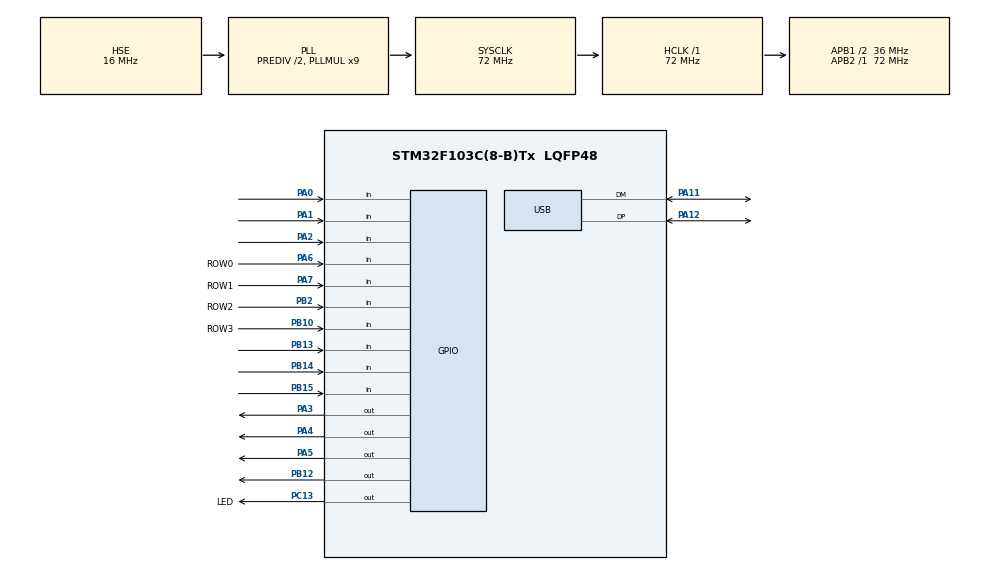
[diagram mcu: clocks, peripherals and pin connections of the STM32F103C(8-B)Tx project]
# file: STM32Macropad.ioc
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Mcu.Family=STM32F1
Mcu.Name=STM32F103C(8-B)Tx
Mcu.Package=LQFP48
NVIC.PriorityGroup=NVIC_PRIORITYGROUP_4
NVIC.USB_LP_CAN1_RX0_IRQn=true\:0\:0\:false\:false\:true\:false\:true\:true
PA0-WKUP.Signal=GPIO_Input
PA1.Signal=GPIO_Input
PA11.Mode=Device
PA11.Signal=USB_DM
PA12.Mode=Device
PA12.Signal=USB_DP
PA13.Mode=Serial_Wire
PA13.Signal=SYS_JTMS-SWDIO
PA14.Mode=Serial_Wire
PA14.Signal=SYS_JTCK-SWCLK
PA2.Signal=GPIO_Input
PA3.Signal=GPIO_Output
PA4.Signal=GPIO_Output
PA5.Signal=GPIO_Output
PA6.GPIO_Label=ROW0
PA6.GPIO_PuPd=GPIO_PULLUP
PA6.Signal=GPIO_Input
PA7.GPIO_Label=ROW1
PA7.GPIO_PuPd=GPIO_PULLUP
PA7.Signal=GPIO_Input
PB10.GPIO_Label=ROW3
PB10.GPIO_PuPd=GPIO_PULLUP
PB10.Signal=GPIO_Input
PB12.Signal=GPIO_Output
PB13.Signal=GPIO_Input
PB14.Signal=GPIO_Input
PB15.Signal=GPIO_Input
PB2.GPIO_Label=ROW2
PB2.GPIO_PuPd=GPIO_PULLUP
PB2.Signal=GPIO_Input
PC13-TAMPER-RTC.GPIO_Label=LED
PC13-TAMPER-RTC.Signal=GPIO_Output
PD0-OSC_IN.Mode=HSE-External-Oscillator
PD0-OSC_IN.Signal=RCC_OSC_IN
PD1-OSC_OUT.Mode=HSE-External-Oscillator
PD1-OSC_OUT.Signal=RCC_OSC_OUT
ProjectManager.HeapSize=0x200
ProjectManager.StackSize=0x400
ProjectManager.TargetToolchain=Makefile
RCC.AHBFreq_Value=72000000
RCC.APB1CLKDivider=RCC_HCLK_DIV2
RCC.APB1Freq_Value=36000000
RCC.APB1TimFreq_Value=72000000
RCC.APB2Freq_Value=72000000
RCC.APB2TimFreq_Value=72000000
RCC.HCLKFreq_Value=72000000
RCC.HSEDivPLL=RCC_HSE_PREDIV_DIV2
RCC.HSE_VALUE=16000000
RCC.PLLMUL=RCC_PLL_MUL9
RCC.SYSCLKFreq_VALUE=72000000
RCC.SYSCLKSource=RCC_SYSCLKSOURCE_PLLCLK
RCC.USBFreq_Value=48000000
RCC.USBPrescaler=RCC_USBCLKSOURCE_PLL_DIV1_5
USB_DEVICE.CLASS_NAME_FS=HID
USB_DEVICE.PRODUCT_STRING_HID_FS=FUCK ME BAYLE\!
USB_DEVICE.VirtualMode=Hid
USB_DEVICE.VirtualModeFS=Hid_FS
VP_USB_DEVICE_VS_USB_DEVICE_HID_FS.Mode=HID_FS
board=custom

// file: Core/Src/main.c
#include "main.h"
#include "usb_device.h"
#include "led.h"
#include "keypad.h"

/* USER CODE BEGIN PD */

// Define the timing constants (in clock cycles)
#define T0H  1  // 0.32 µs
#define T1H  3  // 0.64 µs
#define T0L  3   // 0.8 µs
#define T1L  1   // 0.2 µs
#define TRST 5000    // >80 µs

/* USER CODE END PD */

/* USER CODE BEGIN PV */
uint16_t led_data[NUM_LEDS][3]; // Assuming 24 bits per LED
/* USER CODE END PV */

void SystemClock_Config(void);
static void MX_GPIO_Init(void);

/* USER CODE BEGIN 0 */
void cycle_colors(void) {
    static uint8_t color_index = 0;
    uint8_t colors[3][3] = {
        {255, 0, 0},   // Red
        {0, 255, 0},   // Green
        {0, 0, 255}    // Blue
    };

    for (uint8_t i = 0; i < NUM_LEDS; i++) {
        set_led_color(i, colors[color_index][0], colors[color_index][1], colors[color_index][2]);
    }

    color_index = (color_index + 1) % 3;
}
/* USER CODE END 0 */

int main(void)
{
    /* USER CODE BEGIN 1 */
    __set_CONTROL(0);
    __ISB();

    /* USER CODE END 1 */

    /* MCU Configuration--------------------------------------------------------*/

    /* Reset of all peripherals, Initializes the Flash interface and the Systick. */
    HAL_Init();

    /* Configure the system clock */
    SystemClock_Config();

    /* Initialize all configured peripherals */
    MX_GPIO_Init();
    MX_USB_DEVICE_Init();
    /* USER CODE BEGIN 2 */
    for (uint8_t i = 0; i < NUM_LEDS; i++)
    {
      set_led_color(i, 255, 0, 0); // Set all LEDs to red
    }

    char key;

    /* USER CODE END 2 */

    /* Infinite loop */
    /* USER CODE BEGIN WHILE */
    while (1)
    {
      key = Keypad_Scan();

      if (key != '\0')
      {
        Keypad_SendKeyViaUSB(key);
        HAL_Delay(150);
      }
      // __disable_irq();
      // cycle_colors(); // Cycle through colors
      // update_leds(); // Update all LEDs
      // __enable_irq();
      // HAL_Delay(1000);
    /* USER CODE END WHILE */
    }
}

void SystemClock_Config(void)
{
  RCC_OscInitTypeDef RCC_OscInitStruct = {0};
  RCC_ClkInitTypeDef RCC_ClkInitStruct = {0};
  RCC_PeriphCLKInitTypeDef PeriphClkInit = {0};

  /** Initializes the RCC Oscillators according to the specified parameters
  * in the RCC_OscInitTypeDef structure.
  */
  RCC_OscInitStruct.OscillatorType = RCC_OSCILLATORTYPE_HSE;
  RCC_OscInitStruct.HSEState = RCC_HSE_ON;
  RCC_OscInitStruct.HSEPredivValue = RCC_HSE_PREDIV_DIV2;
  RCC_OscInitStruct.HSIState = RCC_HSI_ON;
  RCC_OscInitStruct.PLL.PLLState = RCC_PLL_ON;
  RCC_OscInitStruct.PLL.PLLSource = RCC_PLLSOURCE_HSE;
  RCC_OscInitStruct.PLL.PLLMUL = RCC_PLL_MUL9;
  if (HAL_RCC_OscConfig(&RCC_OscInitStruct) != HAL_OK)
  {
    Error_Handler();
  }

  /** Initializes the CPU, AHB and APB buses clocks
  */
  RCC_ClkInitStruct.ClockType = RCC_CLOCKTYPE_HCLK|RCC_CLOCKTYPE_SYSCLK
                              |RCC_CLOCKTYPE_PCLK1|RCC_CLOCKTYPE_PCLK2;
  RCC_ClkInitStruct.SYSCLKSource = RCC_SYSCLKSOURCE_PLLCLK;
  RCC_ClkInitStruct.AHBCLKDivider = RCC_SYSCLK_DIV1;
  RCC_ClkInitStruct.APB1CLKDivider = RCC_HCLK_DIV2;
  RCC_ClkInitStruct.APB2CLKDivider = RCC_HCLK_DIV1;

  if (HAL_RCC_ClockConfig(&RCC_ClkInitStruct, FLASH_LATENCY_2) != HAL_OK)
  {
    Error_Handler();
  }
  PeriphClkInit.PeriphClockSelection = RCC_PERIPHCLK_USB;
  PeriphClkInit.UsbClockSelection = RCC_USBCLKSOURCE_PLL_DIV1_5;
  if (HAL_RCCEx_PeriphCLKConfig(&PeriphClkInit) != HAL_OK)
  {
    Error_Handler();
  }
}

static void MX_GPIO_Init(void)
{
  GPIO_InitTypeDef GPIO_InitStruct = {0};

  /* GPIO Ports Clock Enable */
  __HAL_RCC_GPIOC_CLK_ENABLE();
  __HAL_RCC_GPIOD_CLK_ENABLE();
  __HAL_RCC_GPIOA_CLK_ENABLE();
  __HAL_RCC_GPIOB_CLK_ENABLE();

  /*Configure GPIO pin Output Level */
  HAL_GPIO_WritePin(LED_GPIO_Port, LED_Pin, GPIO_PIN_RESET);

  /*Configure GPIO pin Output Level */
  HAL_GPIO_WritePin(GPIOA, GPIO_PIN_3|GPIO_PIN_4|GPIO_PIN_5, GPIO_PIN_RESET);

  /*Configure GPIO pin Output Level */
  HAL_GPIO_WritePin(GPIOB, GPIO_PIN_12, GPIO_PIN_RESET);

  /*Configure GPIO pin : LED_Pin */
  GPIO_InitStruct.Pin = LED_Pin;
  GPIO_InitStruct.Mode = GPIO_MODE_OUTPUT_PP;
  GPIO_InitStruct.Pull = GPIO_NOPULL;
  GPIO_InitStruct.Speed = GPIO_SPEED_FREQ_HIGH;
  HAL_GPIO_Init(LED_GPIO_Port, &GPIO_InitStruct);

  /*Configure GPIO pins : PA0 PA1 PA2 */
  GPIO_InitStruct.Pin = GPIO_PIN_0|GPIO_PIN_1|GPIO_PIN_2;
  GPIO_InitStruct.Mode = GPIO_MODE_INPUT;
  GPIO_InitStruct.Pull = GPIO_NOPULL;
  HAL_GPIO_Init(GPIOA, &GPIO_InitStruct);

  /*Configure GPIO pins : PA3 PA4 PA5 PA6 */
  GPIO_InitStruct.Pin = COL3_Pin|COL2_Pin|COL1_Pin|COL0_Pin;
  GPIO_InitStruct.Mode = GPIO_MODE_OUTPUT_PP;
  GPIO_InitStruct.Pull = GPIO_NOPULL;
  GPIO_InitStruct.Speed = GPIO_SPEED_FREQ_LOW;
  HAL_GPIO_Init(GPIOA, &GPIO_InitStruct);
  HAL_GPIO_WritePin(GPIOA, COL3_Pin | COL2_Pin | COL1_Pin | COL0_Pin, GPIO_PIN_SET);

  /*Configure GPIO pins : ROW0_Pin ROW1_Pin */
  GPIO_InitStruct.Pin = ROW0_Pin;
  GPIO_InitStruct.Mode = GPIO_MODE_INPUT;
  GPIO_InitStruct.Pull = GPIO_PULLUP;
  HAL_GPIO_Init(GPIOA, &GPIO_InitStruct);

  /*Configure GPIO pins : ROW2_Pin ROW3_Pin */
  GPIO_InitStruct.Pin = ROW1_Pin|ROW2_Pin|ROW3_Pin;
  GPIO_InitStruct.Mode = GPIO_MODE_INPUT;
  GPIO_InitStruct.Pull = GPIO_PULLUP;
  HAL_GPIO_Init(GPIOB, &GPIO_InitStruct);

  /*Configure GPIO pin : PB12 */
  GPIO_InitStruct.Pin = GPIO_PIN_12;
  GPIO_InitStruct.Mode = GPIO_MODE_OUTPUT_PP;
  GPIO_InitStruct.Pull = GPIO_NOPULL;
  GPIO_InitStruct.Speed = GPIO_SPEED_FREQ_LOW;
  HAL_GPIO_Init(GPIOB, &GPIO_InitStruct);

  /*Configure GPIO pins : PB13 PB14 PB15 */
  GPIO_InitStruct.Pin = GPIO_PIN_13|GPIO_PIN_14|GPIO_PIN_15;
  GPIO_InitStruct.Mode = GPIO_MODE_INPUT;
  GPIO_InitStruct.Pull = GPIO_NOPULL;
  HAL_GPIO_Init(GPIOB, &GPIO_InitStruct);

}

void Error_Handler(void)
{
  __disable_irq();
  while (1)
  {
  }
}
